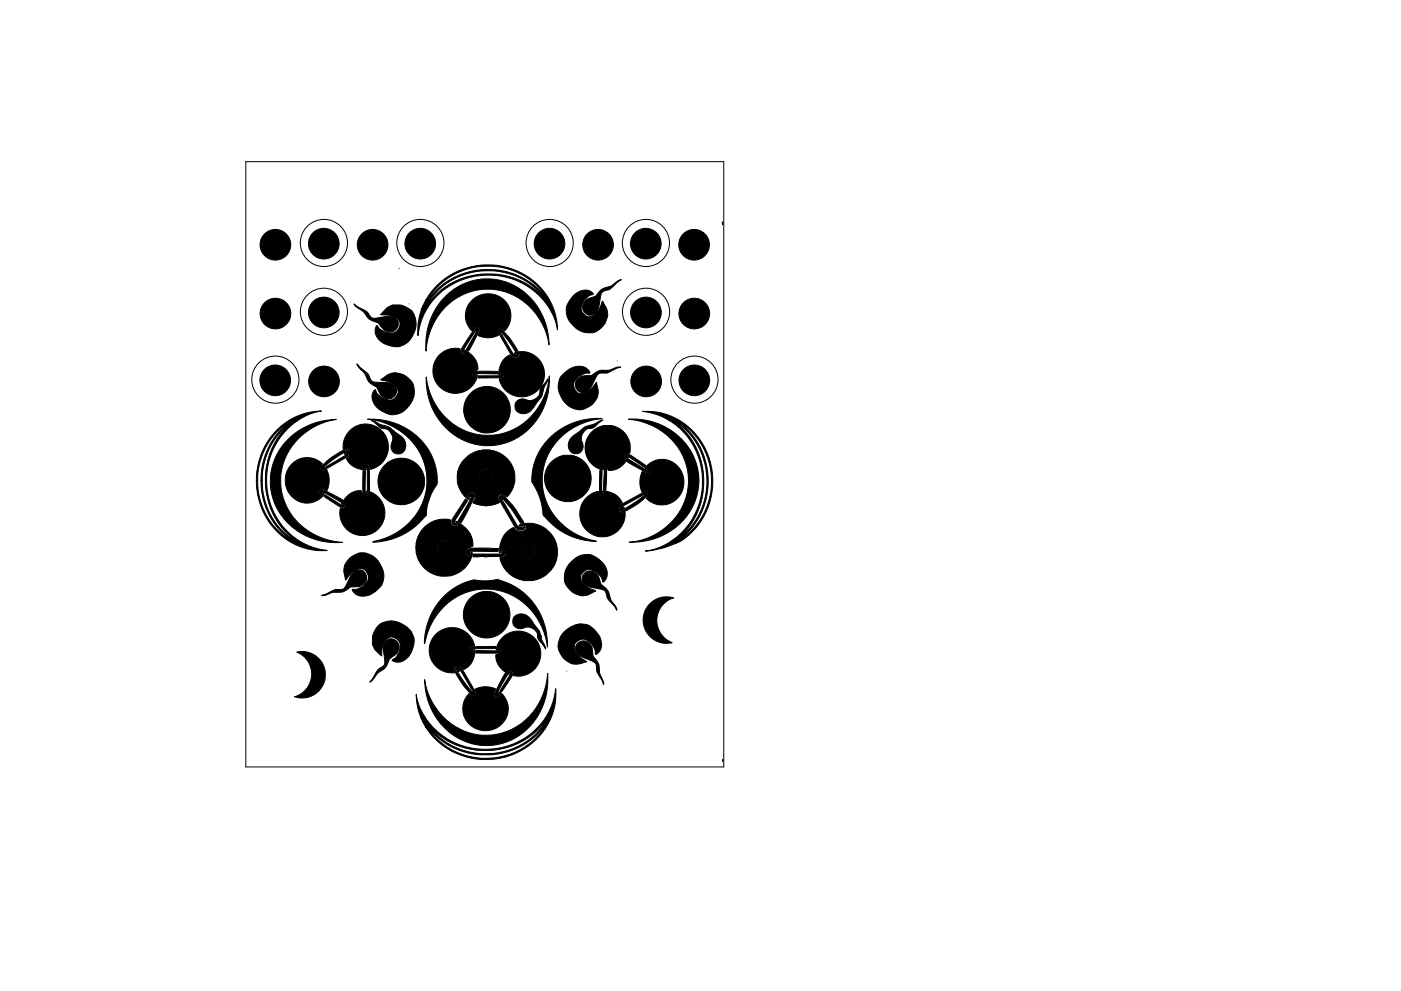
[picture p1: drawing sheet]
<svg xmlns="http://www.w3.org/2000/svg" width="297mm" height="210mm" viewBox="0 0 297 210" stroke-linecap="round" stroke-linejoin="round" font-family="sans-serif">
<g fill="none" stroke="#000" stroke-width=".21">
<path d="M52.1 34.3h101.4v128.4h-101.4z"/>
<circle cx="68.7" cy="51.5" r="5"/>
<circle cx="89.1" cy="51.5" r="5"/>
<circle cx="116.5" cy="51.5" r="5"/>
<circle cx="136.9" cy="51.5" r="5"/>
<circle cx="68.7" cy="66.1" r="5"/>
<circle cx="137" cy="66.1" r="5"/>
<circle cx="58.4" cy="80.5" r="5"/>
<circle cx="147.2" cy="80.5" r="5"/>
</g>
<g fill="#000" stroke="#000" stroke-width=".21">
<path d="M94.7 62.6a12.6 12.6 0 0 1 20.3 4.2 15.8 15.8 0 0 1 1.4 6.4 13.3 13.3 0 0 0-15.5-11.6 13.8 13.8 0 0 0-10.6 12.9 14.6 14.6 0 0 1 4.4-11.9zM102.4 59.5h1.5v1.5h-1.5zM124.2 63.7l1.1-.5a2.5 2.5 0 0 0 1.9-1.5l.8-.5a5 5 0 0 0 3-1.6l.7-.3-1.1 .9a3.8 3.8 0 0 1-2.7 1.6 2.24 2.24 0 0 0-.7 1.9 3.7 3.7 0 0 1-1.2 2.9 1.7 1.7 0 0 1-2.3-.6 1.7 1.7 0 0 1 .5-2.3zM153.2 47.1l.1 .6zM75.1 64.5l.5 .4a7.3 7.3 0 0 1 2.6 1.7 1.37 1.37 0 0 0 1.9 .9l1-.2a2.68 2.68 0 0 1 3 .5 1.75 1.75 0 0 1-.5 2.4 1.75 1.75 0 0 1-2.3-.3l-1.1-1.4a4.2 4.2 0 0 1-3.1-2.4l-1.6-1zM75.7 77.2l.7 .8a4.6 4.6 0 0 1 2.3 2.8 3.7 3.7 0 0 0 2.5 .3 2.41 2.41 0 0 1 2.9 1.9 1.96 1.96 0 0 1-2 1.6 1.96 1.96 0 0 1-1.9-1.7l-.3-.7a4.2 4.2 0 0 1-2.5-2.9l-.7-.7a2.29 2.29 0 0 1-1-1.4zM82.2 67.9h1v1.5h-1zM80.8 80.5a4.8 4.8 0 0 1 3.3-1.4 4.1 4.1 0 0 1 3.6 2.7 4.1 4.1 0 0 1-1.1 4.4 4.1 4.1 0 0 1-6.1 .7 2.82 2.82 0 0 1-1-4.2h.1a3.5 3.5 0 0 0 3.5 2.1 1.71 1.71 0 0 0 1.3-1.3 1.71 1.71 0 0 0-.8-1.8 6.8 6.8 0 0 0-2.9-1.1zM81.9 65.5l.6-.5a2.37 2.37 0 0 1 2.1-.3 3.9 3.9 0 0 1 3.2 5.8 4.2 4.2 0 0 1-6.3 2.4 2.85 2.85 0 0 1-1.9-3.4l.3-.4a3.7 3.7 0 0 0 3.9 1.4 1.71 1.71 0 0 0 .3-3 6.5 6.5 0 0 0-3.4-.8zM83.7 71.5h1v1h-1zM89.7 64.8h1v.5h-1zM92.7 60.5a15.3 15.3 0 0 1 24.5 4.5 13.9 13.9 0 0 1 1 4.9 13.7 13.7 0 0 0-9.6-10.7 15.1 15.1 0 0 0-19.5 9.4l-.5 2.6v-1.5a11.8 11.8 0 0 1 1.1-4.8h.7a16.2 16.2 0 0 1 24.9-1.8 15.2 15.2 0 0 0-24.9 1.7l-.7 .1 .6-1.2h.3a15.9 15.9 0 0 1 25.1-.7 14.9 14.9 0 0 0-25.1 .7h-.3l1.3-2z"/>
<path d="M93.4 75.1a3.9 3.9 0 0 1 4.1-1 .78 .78 0 0 0 .5 1 .78 .78 0 0 0 1-.4l-.5-.4a4.1 4.1 0 0 1 2.7 4.2 1.02 1.02 0 0 0-1 1.3 .47 .47 0 0 0 .6 .2 .47 .47 0 0 0 .2-.6h.1a1.7 1.7 0 0 1-.5 1.9 4.8 4.8 0 0 1-7.2 1 4.8 4.8 0 0 1 0-7.2zM97.7 79.1h1.5v1.5h-1.5zM100.1 70.6l.3 .2-2.1 3.5v.2l.5 .3a.67 .67 0 0 1-1-.2 .67 .67 0 0 1 .2-.9zM100.6 69.8a.57 .57 0 0 1 .9 0 .57 .57 0 0 1-.1 .8l-1.6 3.2-.6 .7-.4-.3 2.2-3.7a.45 .45 0 0 0-.5-.6zM100.4 79.1a8.9 8.9 0 0 1 4-.3h1.2l-.1 .4-.1 .1h-1.1a9.2 9.2 0 0 0-3.6 .1v.6a.51 .51 0 0 1-.5-.4 .51 .51 0 0 1 .2-.5zM99.9 63.9a4.8 4.8 0 0 1 6.6-.6 4.8 4.8 0 0 1 .7 6.7l-.2 .2a.79 .79 0 0 0-.8-.5 .79 .79 0 0 0-.7 .7v.2a.4 .4 0 0 0 .7 0v.1a4.4 4.4 0 0 1-3.9 .8l-.9-.4a1.01 1.01 0 0 0-.1-1.7l-.5 .1-.5 .4 .5 .5-.1 .2a4.3 4.3 0 0 1-.8-6.7zM102.8 64.3h1.4v1.5h-1.4zM101.3 79.7h4.3a.35 .35 0 0 0 .3 .1 .35 .35 0 0 0 .3-.3v-.4a.53 .53 0 0 1 .6 .6 .53 .53 0 0 1-.8 .4l-4.7 .1zM105.8 70.1a.71 .71 0 0 1 1.1 .3l1.2 1.5 1.7 2.6a.41 .41 0 0 1-.7-.2l-1.4-2.1-1.5-1.8a.31 .31 0 0 1-.5 .2 .31 .31 0 0 1 .1-.5zM106.1 71.2l.1-.2a1.84 1.84 0 0 1 .9 1.3l1.4 2.3a1 1 0 0 0 1.6 .6 1 1 0 0 1-1 .5 1 1 0 0 1-.9-.7zM106.9 76.2l.3-.3a.99 .99 0 0 1 1-.5 1.08 1.08 0 0 0 1.2 .6 1.08 1.08 0 0 0 .9-1h-1.3a2.39 2.39 0 0 1 2.4-.4 4.8 4.8 0 0 1 2.7 8.1 4.8 4.8 0 0 1-8.2-2.3 .72 .72 0 0 0 .9-.4 .72 .72 0 0 0-.2-.9l-.5-.2-.2 .6a1.21 1.21 0 0 1 0-1.3l.4-1.2zM110.8 77.9h1.6v1.5h-1.6z"/>
<path d="M90.4 80a13.4 13.4 0 0 0 13.4 12.4 13.4 13.4 0 0 0 12.7-12.6 14.2 14.2 0 0 1-9.4 14.2 13.1 13.1 0 0 1-15.9-8.6 14.5 14.5 0 0 1-.8-5.4zM119.4 79.4a4 4 0 0 1 5-1.2 .78 .78 0 0 1 .6 1 3.4 3.4 0 0 0-3.4 2.4 1.71 1.71 0 0 0 2 1.9 5.5 5.5 0 0 0 2.9-2.4v.1a4.1 4.1 0 0 1-.2 3.6 4.1 4.1 0 0 1-4.1 2 4.1 4.1 0 0 1-3.4-3 3.8 3.8 0 0 1 .6-4.4zM121.8 62.5a2.71 2.71 0 0 1 4-.2v.1a3.5 3.5 0 0 0-2.5 3.5 1.7 1.7 0 0 0 2.2 1.2 5.7 5.7 0 0 0 2.3-3.2 4.9 4.9 0 0 1 1 3.3 4.1 4.1 0 0 1-3 3.4 4.1 4.1 0 0 1-4.3-1.6 4.1 4.1 0 0 1 0-6.2zM123.9 68.7h.8v.8h-.8zM124.3 64.3h1.5v1.5h-1.5zM122.5 80.4a2.36 2.36 0 0 1 2.3-.7h.6a3.9 3.9 0 0 1 3.6-1.2h.2a3.7 3.7 0 0 1 2.4-.6l-1.5 .6a3.9 3.9 0 0 1-2.4 .6 1.52 1.52 0 0 0-1.6 1.4l-.1 .3a3.2 3.2 0 0 1-2.5 2.5 1.68 1.68 0 0 1-1.4-1.2 1.68 1.68 0 0 1 .4-1.7zM61.5 89.1h.6v.6h-.6zM61.8 98.5a4.6 4.6 0 0 1 6.6-.1 .79 .79 0 0 0-.5 .8 .79 .79 0 0 0 .6 .7h.2a.4 .4 0 0 0 .1-.7 4.5 4.5 0 0 1 .7 4.5l-.2 .4a1.01 1.01 0 0 0-1.7 0l.1 .5 .4 .5 .5-.5a1.24 1.24 0 0 1-.9 1.3 4.7 4.7 0 0 1-6.1-.8 4.7 4.7 0 0 1-.1-6.2zM61.1 93.2a14.6 14.6 0 0 1 10.2-4.2 13.3 13.3 0 0 0-11.5 15.5 13.7 13.7 0 0 0 12.8 10.6 13.7 13.7 0 0 1-15.3-12.1 12.5 12.5 0 0 1 3.8-9.8zM68.4 98.7l1.8-1.6 2.4-1.4a.35 .35 0 0 1 .2 .3 .35 .35 0 0 1-.3 .3l-1.9 1.2-2 1.7a.31 .31 0 0 1 .1 .5 .31 .31 0 0 1-.5-.1l-.2-.3zM69.1 99.1l3.7-2.2a1 1 0 0 0 .5-1.6 1.01 1.01 0 0 1 .6 1 1.01 1.01 0 0 1-.8 .9l-3.7 2.2zM77 99.8l.5 .1v1.2a9.1 9.1 0 0 0 .1 3.6 .31 .31 0 0 1 .5 0 .31 .31 0 0 1-.3 .5 .79 .79 0 0 1-.9-1.2z"/>
<path d="M77.4 98.8a.62 .62 0 0 1 .7 .1 .62 .62 0 0 1 .2 .7v4.5h-.4v-4.3a.35 .35 0 0 0 0-.3 .35 .35 0 0 0-.3-.3h-.3zM74.2 91.4a4.8 4.8 0 0 1 7.6 1.1 4.8 4.8 0 0 1-3.3 7 .72 .72 0 0 0-.3-.9 .72 .72 0 0 0-.9 .2l-.2 .5 .6 .3a4.2 4.2 0 0 1-4.2-2.3 1.15 1.15 0 0 0 .6-1.2 1.15 1.15 0 0 0-.8-1 .93 .93 0 0 0 0 1.2l-.1 .1a3.3 3.3 0 0 1-.1-3.6zM77.9 88.9h.1a14.4 14.4 0 0 1 13.8 8.5 12.6 12.6 0 0 1 .9 5.1l-.1 .4a11.2 11.2 0 0 0-2.2 6.4 14.5 14.5 0 0 1-11.4 5.7 13.5 13.5 0 0 0 11.5-12.6 13.4 13.4 0 0 0-12.6-13.4zM78.7 89.2l.8 .2 1 .6a5.3 5.3 0 0 1 3.5 1.9 2.89 2.89 0 0 1 1.9 3.4 1.6 1.6 0 0 1-2.3 .8 1.6 1.6 0 0 1-.5-2.3 2.26 2.26 0 0 0-2.3-3zM78 93h1.4v1.5h-1.4zM81.2 82.1h1.5v1.5h-1.5zM84.6 93.8h.5v1h-.5zM84.9 81.5h.8v.8h-.8zM102.8 86.1h1.5v1.5h-1.5zM105.6 92.2h1.5v1.5h-1.5zM110.9 85.3h.5v1h-.5zM115.5 94.6h.6v.6h-.6z"/>
<path d="M109.6 85.1a2.07 2.07 0 0 1 2.4-.1 2.24 2.24 0 0 0 2.5-2.5l1.7-2.2-.2 .8-.6 1a5 5 0 0 1-1.6 3.4 3.3 3.3 0 0 1-3.2 2.2 1.57 1.57 0 0 1-1.3-1 1.57 1.57 0 0 1 .3-1.6zM120.5 83.1h.8v.8h-.8zM121.8 94.2h1v.5h-1zM123.1 80.7h1v1h-1zM116.2 93.2a14.4 14.4 0 0 1 11.5-4.4 13.7 13.7 0 0 0-12.7 12.4 13.6 13.6 0 0 0 11.4 13.6h.1a14 14 0 0 1-11.4-5.7v-.6a13.3 13.3 0 0 0-2.3-6.3l-.1-.6a12.5 12.5 0 0 1 3.5-8.4zM127.2 99.8h.4v4.7a.39 .39 0 0 1 .5 .3 .55 .55 0 0 1-.7 .3 .55 .55 0 0 1-.3-.7zM121.3 92.7l2.7-2.1 2-.6 1.8-.9-1.1 .8a2.26 2.26 0 0 1-2.1 1.1 2.24 2.24 0 0 0-1.1 3.1 1.6 1.6 0 0 1-1.4 2.2 1.6 1.6 0 0 1-1.6-2.1l.2-.8zM127.6 98.8l.1-.1a.75 .75 0 0 1 .9 1l-.1 3.8a.36 .36 0 0 1-.1 .5 .36 .36 0 0 1-.4 0l.1-4.7-.6-.1zM127.6 93h1.5v1.5h-1.5zM125.4 91.7a4.8 4.8 0 0 1 5.8-.9 4.8 4.8 0 0 1 2.3 5.3 .85 .85 0 0 0-1.1 1.1l.3 .3 .5-.5a4.1 4.1 0 0 1-4.3 2.7 1.12 1.12 0 0 0-1.2-1.1 .45 .45 0 0 0-.4 .5 .45 .45 0 0 0 .7 .3v.2a4.1 4.1 0 0 1-3.9-3.7 4.7 4.7 0 0 1 1.3-4.2zM133.2 97.4l3.8 2.3h.2l.3-.5a.61 .61 0 0 1 .2 .9 .61 .61 0 0 1-1 0l-3.7-2.1a.38 .38 0 0 1 .2-.6zM132.6 96.6a1.17 1.17 0 0 1 1.6 .3l2.7 1.9-.2 .3-3.5-2.2h-.3l-.2 .4a.47 .47 0 0 1-.1-.7z"/>
<path d="M133.3 88.9a13.5 13.5 0 0 1 14.8 14.2 13.8 13.8 0 0 1-14 11.9h-.7a13.6 13.6 0 0 0 12.6-12.7 13.6 13.6 0 0 0-12.7-13.4zM137.3 98.7a4.6 4.6 0 0 1 5.3-.7 4.6 4.6 0 0 1 2.4 4.9 4.5 4.5 0 0 1-3.1 4 4.5 4.5 0 0 1-4.8-1.3 .71 .71 0 0 0 .4-.9 .71 .71 0 0 0-1-.4l.1 .7a4.3 4.3 0 0 1-.4-4.9v-.1a1.05 1.05 0 0 0 1.8 0l-.1-.3a.57 .57 0 0 0-.5-.6l-.6 .4zM141.8 88.7h1v.5h-1zM146.2 99.7h1.5v1.5h-1.5zM58.7 91.2a13.3 13.3 0 0 1 9.5-4h-.1a13.7 13.7 0 0 0-10.8 9.6 15.1 15.1 0 0 0 9.2 19.4l2.9 .6a13.9 13.9 0 0 1-14.5-10.8l-.5-3v-1h.2a14.4 14.4 0 0 0 7.2 12.7 15.5 15.5 0 0 1-6.5-12.8h.3a14.5 14.5 0 0 0 7.5 13.1 16.2 16.2 0 0 1-1.9-24.9 14.4 14.4 0 0 0-5.6 11.8h-.3a15.5 15.5 0 0 1 5.8-12.2 14.3 14.3 0 0 0-6.5 12.3h-.2a15.1 15.1 0 0 1 4.3-10.8zM57.6 101h1.5v1.5h-1.5zM64.3 101.3h1.5v1.5h-1.5zM67.9 103.9l.3-.1 .6 .2 3.1 1.6 .7 .6-.2 .4-3.8-2.2a.45 .45 0 0 0-.5 .5 .62 .62 0 0 1-.2-1zM68.9 105l3.5 2.1h.3l.3-.4a.67 .67 0 0 1-.3 .9 .67 .67 0 0 1-.9-.2l-3.1-2.1zM73.7 105.1a3.1 3.1 0 0 1 2.9-.9 1.02 1.02 0 0 0 1.4 1 .47 .47 0 0 0 .2-.6 .47 .47 0 0 0-.6-.2l-.1-.1a1.7 1.7 0 0 1 1.9 .5 4.8 4.8 0 0 1-.7 8.4 4.8 4.8 0 0 1-6.5-5.3 .78 .78 0 0 0 1-.4 .78 .78 0 0 0-.3-1.1l-.5 .5 .5-.8zM74.2 118.4a4 4 0 0 1 6.5 1.6 4.1 4.1 0 0 1-2 6.1 2.66 2.66 0 0 1-4-1 3.4 3.4 0 0 0 3.4-2.6 1.75 1.75 0 0 0-1-1.7 1.75 1.75 0 0 0-2 .4l-.6 .4-1.2 1.5a4.1 4.1 0 0 1 .3-4zM77.3 108.7h1.5v1.5h-1.5z"/>
<path d="M78.4 119.8h.8v.8h-.8zM86.1 102.1h1.5v1.5h-1.5zM89.8 112l1.5-1.1 1.3-.5a4.9 4.9 0 0 1 2.9 0l.1 .6a.82 .82 0 0 0 .8 .7 .82 .82 0 0 0 .8-.6l-.6-.5 1.4 .8 1.2 1.2 .7 1.2 .3 1.3a.99 .99 0 0 1-1 1.2 .79 .79 0 0 0-.6 1 .79 .79 0 0 0 1.1 .5l.2-.7a.57 .57 0 0 1 .1 .9l-.5 1.2-1 1.3-1 .9-1.3 .5a6.5 6.5 0 0 1-3.9 .1l-1.8-1-1.2-1.3-.8-1.6-.3-1.9h4.4a1.53 1.53 0 0 0 2.1 1.3 1.53 1.53 0 0 0 .5-2.4 1.53 1.53 0 0 0-2.4 .4l-.2 .7h-4.4v-1.1l.4-1.2zM90.9 112.6h.8v.8h-.8zM90.8 100.6h1.5v1.5h-1.5zM93.5 115.5h1.5v1.5h-1.5zM98.5 97.5l.9-.9 .9-.5 2-.6h1.5l1 .2 1.8 .8 1.1 1 .7 .9 .7 2v2l-.5 1.5-.6 1a.51 .51 0 0 1-.7 .4 .89 .89 0 0 0-1.2-.4 .89 .89 0 0 0-.4 1.2h.8l-.4 .4-1 .4-2 .4-1.4-.2-1.3-.4h-.1l.2-.4a1.23 1.23 0 0 0-.1-1.8 1.09 1.09 0 0 0-1.4 .7l.6 .5-.1 .2-.4-.1-.7-.7-1.1-1.7a4.3 4.3 0 0 1-.3-2.4h4.5v.2a1.52 1.52 0 0 0 2.3 1.1 1.52 1.52 0 0 0 0-2.6 1.52 1.52 0 0 0-2.3 1.3h-4.5v-1l.4-1.1zM98.7 105.9a.37 .37 0 0 1 .4 .3 .37 .37 0 0 1-.2 .4l-2.2 3.4a.6 .6 0 0 0-.3 .6 .6 .6 0 0 0 .5 .6h.1a.72 .72 0 0 1-1 .1 .72 .72 0 0 1-.2-.9zM99.4 104.9a.73 .73 0 0 1 1.1 0 .73 .73 0 0 1-.1 1.1l-2.2 4.2a.75 .75 0 0 1-.6 .7l-.2-.1a.35 .35 0 0 1-.3-.3 .35 .35 0 0 1 .3-.4l2.3-4a.41 .41 0 0 0 .2-.5 .41 .41 0 0 0-.4-.3l-.2-.1zM99 116.7l.4-.3 .9-.1 5.4 .1-.2 .6h-5.4a.38 .38 0 0 0-.5 0 .38 .38 0 0 0 0 .5 .37 .37 0 0 1-.5 .3 .37 .37 0 0 1-.2-.5zM102.6 105h.8v.8h-.8zM102.2 100.3h1.5v1.5h-1.5z"/>
<path d="M105.9 105.3a.64 .64 0 0 1 1 0l2.2 2.5 1.7 2.6a.36 .36 0 0 1-.1 .6 .36 .36 0 0 1-.5-.3l-1.7-2.6-2-2.4a.38 .38 0 0 1-.5 .2 .38 .38 0 0 1-.2-.5zM100.3 117.6h6l.1-.9a.69 .69 0 0 1 .7 .9 .69 .69 0 0 1-.9 .5l-5.9 .1zM106.4 106.6a.32 .32 0 0 1 .4-.1 .32 .32 0 0 1 .1 .3l2.4 4.2a1.33 1.33 0 0 0 2 .8h.1a1.27 1.27 0 0 1-1.3 .7 1.27 1.27 0 0 1-1.1-1l-2.7-4.7zM107.5 112.9l.8-.7a.48 .48 0 0 1 .6-.3 .48 .48 0 0 1 .4 .5l.8 .3a1.11 1.11 0 0 0 1.5-1.1h-1.6a4 4 0 0 1 3.6-.4l1.6 .6 .8 .7 1.4 1.5 .6 1.4 .2 1.4-.2 2-.7 1.5-.8 1-1.3 1-1.2 .6-1 .3-2-.1-1.7-.5-1.3-.8-1.1-1.3-.8-1.8a.32 .32 0 0 1-.1-.4 .32 .32 0 0 1 .4-.1 .82 .82 0 0 0 .9-.4 .82 .82 0 0 0-.2-1h3.4v.2a1.52 1.52 0 0 0 2.3 1.2 1.52 1.52 0 0 0 0-2.6 1.52 1.52 0 0 0-2.3 1.2h-3.4l-.7-.2-.3 .5-.2 .2v-1l.4-1.5 .6-1.2zM108.5 114.5h.7v.8h-.7zM111.3 116h1.5v1.5h-1.5zM118.8 100.9h1.5v1.5h-1.5zM123 119.2h.8v.8h-.8zM121 119.3a4.2 4.2 0 0 1 6.9 .2 2.67 2.67 0 0 1 0 4 3.3 3.3 0 0 0-3.4-2.6 1.76 1.76 0 0 0-1.4 1.8 4.6 4.6 0 0 0 3.2 2.7h-.1a4.1 4.1 0 0 1-3.3 .9 4 4 0 0 1-3.2-2.9 4 4 0 0 1 1.3-4.1zM124.3 105.6a3 3 0 0 1 2.6-1.3 .69 .69 0 0 0 .3 .9 .69 .69 0 0 0 .9-.2l.2-.4-.6-.3a4.2 4.2 0 0 1 4.3 2.4 1.2 1.2 0 0 0-.2 2.1h.2a1.07 1.07 0 0 0 0-1.2h.2a4.8 4.8 0 0 1-3.7 6.3 4.8 4.8 0 0 1-5.6-4.7l.3-1.9zM126.7 107.3h1.5v1.5h-1.5zM131.7 107.1l4.3-2.4 .3 .3-3.2 1.8a1.51 1.51 0 0 0-1.2 .9l.1 1a.92 .92 0 0 1-.3-1.6z"/>
<path d="M132.6 107.8l2.4-1.5 1.8-1.4a.29 .29 0 0 1-.2-.3 .29 .29 0 0 1 .3-.3h.1a.61 .61 0 0 1 .4 .6 .61 .61 0 0 1-.5 .6 17.4 17.4 0 0 1-4.2 2.9zM140.3 101.8h1.5v1.5h-1.5zM136.3 87.3a14.3 14.3 0 0 1 14.8 14.8 14.1 14.1 0 0 1-8 13.2l-2.4 1-2.7 .5-1.1 .1a11.8 11.8 0 0 0 5.6-2.2h1.4a14.9 14.9 0 0 0 .1-25.2 15.8 15.8 0 0 1-.1 25.2h-1.4a15.4 15.4 0 0 0-.6-25.5h.8a16.2 16.2 0 0 1 1.2 25 15.2 15.2 0 0 0-1.2-25h-.8l-.5-.3a13.8 13.8 0 0 0-5.1-1.6zM62.9 138.4a4.9 4.9 0 0 1 6.1 5 4.9 4.9 0 0 1-6.6 4.4 5 5 0 0 0 3.7-4.5 5 5 0 0 0-3.2-4.9zM75.4 122.1h1v1h-1zM68.2 126.3l1.4-.5a4.3 4.3 0 0 1 3-.8 2.42 2.42 0 0 0 1.2-1.7l.4-.7a2.09 2.09 0 0 1 2.9-1.4 1.93 1.93 0 0 1 .4 2.3 1.93 1.93 0 0 1-2.1 1h-.5a2.86 2.86 0 0 0-1.9 .9l-.6 .2a5.6 5.6 0 0 0-3.5 .7zM80.3 132.7a5 5 0 0 1 7.3 2.3 4.8 4.8 0 0 1-2.7 5.4 1.59 1.59 0 0 1-1.7-.4 3.4 3.4 0 0 0 1.5-3.7 1.7 1.7 0 0 0-2.7-.7 5.3 5.3 0 0 0-1.1 3.6l-.3-.3a3.7 3.7 0 0 1-1.6-3.9l.6-1.4zM82.3 133.3h.8v.8h-.8zM81.8 136.1a1.72 1.72 0 0 1 2.4 0 1.72 1.72 0 0 1 0 2.4l-1 .8a2.44 2.44 0 0 0-1.2 1.9l-.3 .4a8.7 8.7 0 0 0-2.7 2.7l-.6 .4 .9-1.3a4 4 0 0 1 2.1-2.2 2.53 2.53 0 0 0 0-2.1 3.4 3.4 0 0 1 .4-3zM82 136.4h1.5v1.5h-1.5zM93.5 138.6h1.5v1.5h-1.5zM92.2 134.8a4.8 4.8 0 0 1 4.9-1.5 4.8 4.8 0 0 1 3.4 3.7 .72 .72 0 0 0-.8 .3 .72 .72 0 0 0 .2 .9l.4 .2 .3-.6a1.21 1.21 0 0 1 0 1.3 3.6 3.6 0 0 1-2.3 2.9 1.15 1.15 0 0 0-1.1-.6 1.15 1.15 0 0 0-1 .8 .93 .93 0 0 0 1.1 0l.1 .1a2.16 2.16 0 0 1-1.9 .4 4.8 4.8 0 0 1-4.2-2.9 4.8 4.8 0 0 1 .9-5z"/>
<path d="M102.9 128.2h1.5v1.5h-1.5zM99.9 137.4l.4-.2h4.8v.4h-4.2a.42 .42 0 0 0-.6 .1 .42 .42 0 0 0 0 .5 .45 .45 0 0 1-.6-.3 .45 .45 0 0 1 .2-.5zM94.4 126.2a12.9 12.9 0 0 1 6.1-3.2 12.5 12.5 0 0 0 5-.1l.1 .1a14.1 14.1 0 0 1 10.5 14.3 13.4 13.4 0 0 0-15-12.2 14 14 0 0 0-11 11.4 13.2 13.2 0 0 1 4.3-10.3zM105.1 123.6h.5v1h-.5zM100.9 138h1.2a9.1 9.1 0 0 0 3.6-.1 .31 .31 0 0 1 0-.3 .31 .31 0 0 1 .2-.2 .66 .66 0 0 1 .2 .8 .66 .66 0 0 1-.8 .4l-4.4-.1zM108.4 138.1h1.5v1.5h-1.5zM106.6 135.2a4.8 4.8 0 0 1 7.9 2.1 4.8 4.8 0 0 1-5.6 6 .78 .78 0 0 0-.4-1 .78 .78 0 0 0-1 .3l.5 .5a4.1 4.1 0 0 1-2.8-4.2 1.02 1.02 0 0 0 1.1-1.4 .47 .47 0 0 0-.6-.2 .47 .47 0 0 0-.2 .6l-.1 .1a1.7 1.7 0 0 1 .5-1.9zM110.2 131.4h.6v.6h-.6zM109.2 130.7a2.52 2.52 0 0 1 3.8 1.3l.2 .4a5.3 5.3 0 0 1 1.7 3.5l.6 1 .2 .8-.3-.6a4.4 4.4 0 0 1-1.4-2.1 2.26 2.26 0 0 0-3.4-1.6 1.56 1.56 0 0 1-1.7-.8 1.56 1.56 0 0 1 .3-1.9zM121.8 133.9h.8v.8h-.8zM119.5 134.2a4.7 4.7 0 0 1 5.5-1.4 4.6 4.6 0 0 1 2.4 4.9 1.36 1.36 0 0 1-1.1 1.1 3.2 3.2 0 0 0-3-3.2 1.8 1.8 0 0 0-1.5 1.3 1.8 1.8 0 0 0 .6 1.9l1.9 1.7a4 4 0 0 1-4.8-.8 3.8 3.8 0 0 1 0-5.5zM122.3 136.6a1.89 1.89 0 0 1 2.1-.4 1.89 1.89 0 0 1 1.2 1.6 2.78 2.78 0 0 0 1.1 2.6l.2 .5a6.3 6.3 0 0 0 .6 2.8l.5 1.1v.5l-.3-.8a4.8 4.8 0 0 1-1.3-3.2 1.16 1.16 0 0 0-1.1-1.2l-.7-.2a3.3 3.3 0 0 1-2.5-2 1.43 1.43 0 0 1 .2-1.3z"/>
<path d="M123.5 136.9h1v1.5h-1zM123.9 121.7a1.9 1.9 0 0 1 3.2 1.1l.3 1a4.8 4.8 0 0 1 2.1 3.3l1.1 1.7 .2 .7-.3-.6a7.6 7.6 0 0 1-1.9-2.5 1.52 1.52 0 0 0-1.8-1.5l-1.5-.3a1.9 1.9 0 0 1-1.6-2.7zM124.4 122.1h1.5v1.5h-1.5zM137.9 128a4.9 4.9 0 0 1 4.9-1.1 5 5 0 0 0-3.5 4.6 5 5 0 0 0 3.2 4.9 5 5 0 0 1-5.5-2.4 5 5 0 0 1 .9-6zM88.2 147.3l.1 .1a13.7 13.7 0 0 0 9.5 10.8 15.1 15.1 0 0 0 19.4-9.2l.6-2.9a14.3 14.3 0 0 1-13.3 15 15 15 0 0 1-14.2-6.8h.4a14.9 14.9 0 0 0 25.1-.6 15.8 15.8 0 0 1-25.1 .6h-.4h.9a15.2 15.2 0 0 0 24.8-1.8v-.1a16.2 16.2 0 0 1-24.8 1.9h-.9a13.2 13.2 0 0 1-2.1-7zM89.7 152.2h.5v1h-.5zM96.6 142.9h.1a.35 .35 0 0 1 .4-.2 .35 .35 0 0 1 .2 .3l1.3 1.9 1.6 2a.31 .31 0 0 1 .5-.1 .31 .31 0 0 1 0 .5 .75 .75 0 0 1-1.2-.4l-1.2-1.4zM96.6 141.8a1.2 1.2 0 0 1 1.8 .9l2 3.4-.2 .2a1.84 1.84 0 0 1-.9-1.2l-1.4-2.4a1 1 0 0 0-1.5-.5zM99.5 147.1a.79 .79 0 0 0 .8 .5 .79 .79 0 0 0 .6-.6v-.2a.4 .4 0 0 0-.7-.1 4.5 4.5 0 0 1 4.5-.7l.4 .2a1.01 1.01 0 0 0 .1 1.7l.4-.1 .5-.4-.4-.6a4.2 4.2 0 0 1 .9 6.6 4.8 4.8 0 0 1-6.7 .7 4.8 4.8 0 0 1-.7-6.7zM101.9 149.9h1.5v1.5h-1.5zM102.1 156.4h1.5v1.5h-1.5zM107.1 142.9l.5 .2-2.1 3.8a.45 .45 0 0 0 .4 .5 .57 .57 0 0 1-.9 .3 .57 .57 0 0 1 .1-1z"/>
<path d="M107.7 142.5a.7 .7 0 0 1 .9 .3 .7 .7 0 0 1-.2 1l-2 2.9h-.4l2.2-3.6v-.3zM90 144.2a13.4 13.4 0 0 0 14.5 11.7 13.6 13.6 0 0 0 11.6-13 13.7 13.7 0 0 1-12 15.3 13.6 13.6 0 0 1-14.1-14zM153.3 161.1l-.1 .4z"/>
<circle cx="58.4" cy="51.9" r="3.2"/>
<circle cx="68.6" cy="51.7" r="3.2"/>
<circle cx="79" cy="51.9" r="3.3"/>
<circle cx="89.1" cy="51.7" r="3.2"/>
<circle cx="116.5" cy="51.7" r="3.2"/>
<circle cx="126.8" cy="51.9" r="3.3"/>
<circle cx="136.9" cy="51.7" r="3.2"/>
<circle cx="147.2" cy="51.9" r="3.2"/>
<circle cx="58.4" cy="66.5" r="3.2"/>
<circle cx="68.6" cy="66.3" r="3.3"/>
<circle cx="82.4" cy="72.2" r=".4"/>
<circle cx="83.5" cy="69.5" r=".4"/>
<circle cx="89.7" cy="65.7" r=".4"/>
<circle cx="100.2" cy="68.9" r=".4"/>
<circle cx="108.3" cy="61.2" r=".4"/>
<circle cx="114.2" cy="77.2" r=".4"/>
<circle cx="122.1" cy="79.1" r=".4"/>
<circle cx="122.5" cy="63.3" r=".4"/>
<circle cx="125" cy="65.1" r=".4"/>
<circle cx="127.6" cy="68.4" r=".4"/>
<circle cx="136.9" cy="66.3" r="3.2"/>
<circle cx="147.2" cy="66.5" r="3.2"/>
<circle cx="58.3" cy="80.7" r="3.3"/>
<circle cx="62.8" cy="88.9" r=".4"/>
<circle cx="68.7" cy="80.9" r="3.2"/>
<circle cx="75.4" cy="96" r=".4"/>
<circle cx="83.2" cy="91.7" r=".4"/>
<circle cx="83.5" cy="83.5" r=".4"/>
<circle cx="84.7" cy="80.3" r=".4"/>
<circle cx="85.4" cy="94" r=".4"/>
<circle cx="88.7" cy="94.3" r=".4"/>
<circle cx="98.7" cy="87.2" r=".4"/>
<circle cx="99.2" cy="81.3" r=".4"/>
<circle cx="103.3" cy="86.9" r="4.9"/>
<circle cx="108" cy="92.7" r=".4"/>
<circle cx="111.9" cy="85.9" r=".4"/>
<circle cx="114.9" cy="96.5" r=".4"/>
<circle cx="119" cy="92" r=".4"/>
<circle cx="121.3" cy="94.3" r=".4"/>
<circle cx="124.1" cy="85.9" r=".4"/>
<circle cx="124.8" cy="81.6" r=".4"/>
<circle cx="132" cy="93" r=".4"/>
<circle cx="137" cy="80.9" r="3.2"/>
<circle cx="141.3" cy="88.4" r=".4"/>
<circle cx="147.2" cy="80.7" r="3.2"/>
<circle cx="60.6" cy="109.2" r=".4"/>
<circle cx="68.4" cy="102.5" r=".4"/>
<circle cx="77.8" cy="112.2" r=".4"/>
<circle cx="85.1" cy="102.2" r="4.9"/>
<circle cx="86.6" cy="105.3" r=".4"/>
<circle cx="93.8" cy="110.8" r=".4"/>
<circle cx="94.1" cy="116.2" r="1.42"/>
<circle cx="94.7" cy="116.6" r=".4"/>
<circle cx="98.7" cy="103.9" r=".4"/>
<circle cx="102.3" cy="101.2" r=".4"/>
<circle cx="103" cy="101" r="1.42"/>
<circle cx="105.2" cy="106.2" r=".4"/>
<circle cx="107.3" cy="114.1" r=".4"/>
<circle cx="107.8" cy="117.1" r=".4"/>
<circle cx="112" cy="116.8" r=".4"/>
<circle cx="112" cy="116.8" r="1.42"/>
<circle cx="117.2" cy="119.7" r=".4"/>
<circle cx="119.6" cy="105.6" r=".4"/>
<circle cx="120.4" cy="101.5" r="4.9"/>
<circle cx="124.6" cy="118.2" r=".4"/>
<circle cx="129.9" cy="111.8" r=".4"/>
<circle cx="143" cy="101.9" r=".4"/>
<circle cx="143.2" cy="114.8" r=".4"/>
<circle cx="147.1" cy="103.3" r=".4"/>
<circle cx="76.2" cy="123.7" r=".4"/>
<circle cx="79.9" cy="123.5" r=".4"/>
<circle cx="81.2" cy="133.1" r=".4"/>
<circle cx="83.5" cy="136.5" r=".4"/>
<circle cx="84.9" cy="139.9" r=".4"/>
<circle cx="94.8" cy="127" r=".4"/>
<circle cx="100" cy="139" r=".4"/>
<circle cx="103.2" cy="130.4" r="4.9"/>
<circle cx="104.3" cy="134.6" r=".4"/>
<circle cx="113.3" cy="139.9" r=".4"/>
<circle cx="114.4" cy="135" r=".4"/>
<circle cx="121" cy="122.6" r=".4"/>
<circle cx="122.7" cy="133.1" r=".4"/>
<circle cx="122.8" cy="137.4" r=".4"/>
<circle cx="124" cy="123.1" r=".4"/>
<circle cx="126.5" cy="136" r=".4"/>
<circle cx="126.8" cy="121.1" r=".4"/>
<circle cx="139.9" cy="127.8" r=".4"/>
<circle cx="67.6" cy="144.7" r=".4"/>
<circle cx="89.6" cy="152.2" r=".4"/>
<circle cx="90.8" cy="153.9" r=".4"/>
<circle cx="97.1" cy="154.9" r=".4"/>
<circle cx="107.1" cy="149.7" r=".4"/>
</g>
<path d="M143.2 114.8h.1M139.9 127.8l-.5 .5h-.3" fill="none" stroke="#000" stroke-width=".5"/>
<g fill="none" stroke="#000" stroke-width=".6">
<path d="M82.7 68.6l.8 .8M83.5 69.4v.1M84.2 72h-1.7l-.1 .2M90.2 65.1l-.5 .6M98.4 79.9v.6l.8 .8M103.2 60.3h4.1l1 .9M103.5 65.1l-3.3 3.3v.5M114.2 77.2h-1.1l-1.5 1.5M122.1 79.1l-1.2 1.1v3.3l2.5 2.4h.7M122.5 63.3l-1 1v1l2.8 2.8v1h2.6l.7-.7M62.8 88.9l-.5 .5h-.5M78.7 93.7l-2.2 2.3h-1.1"/>
<path d="M82 82.8l.7 .7h.8M83.2 91.7l2.2 2.3h-.2l-.4 .3M84.7 80.3v1l.6 .6M88.7 94.3l2 1.9v4.4l.8 .8M103.6 86.9l-.4 .3h-4.5M108 92.7h-1.4l-.2 .3M111.2 85.8l.7 .1M115.8 94.9l2.8-2.9h.4l-4.1 4v.5M121.3 94.3l.2 .2h.8M123.6 81.2l.5 .4h.7M132 93h-3l-.6 .7M141.3 88.4l.5 .5h.5"/>
<path d="M58.3 101.7v3.3l1.3 1.3v1.9l1 1M65 102l.5 .5h2.9M78 109.5l-.2 .2v2.5M86.8 102.8v2.2l-.2 .3M93.8 110.8l-2.2 2.2h-.3M94.2 116.2h.1M94.3 116.2l.4 .4M98.7 103.9h2.8l1.5 1.5h1.4l.8 .8M107.3 114.1h.7l.8 .8M107.8 117.1l2.5 2.6h6.9M119.5 101.6l.1 4M124.6 118.2v.3l-3.6 3.5v.6"/>
<path d="M127.5 108.1l2.4 2.4v1.3M143 101.9h-1.3l-.7 .7M146.9 100.5v2.7l.2 .1M76 122.6l.2 .2v.9M78.8 120.2v2.2l1.1 1.1M81.3 133.1h.8l.6 .6M83.5 136.5l-.8 .7M84.8 139.6l.1 .3M100 139l-.4 .4h-5.4M103.6 129v5l.7 .6M105.3 124.1h-4.8l-.6 .6h-2.8l-2.3 2.3M109.1 138.8h3.2l1 1.1"/>
<path d="M110.5 131.7h.6M122.7 133.1l-.5 .5v.7M122.8 137.4h1l.2 .3M125.2 122.8l-.3 .3h-.9M126.1 120.4l.7 .7M126.7 135.6l-.2 .4M126.8 121.1h.1M67.4 142.3v2.2l.2 .2M89.6 152.2l.3 .2v.3l.9 .9v.3M97.1 154.9l2.2 2.3h3.5M107.1 149.7l-1 .9h-3.4"/>
</g>
</svg>
